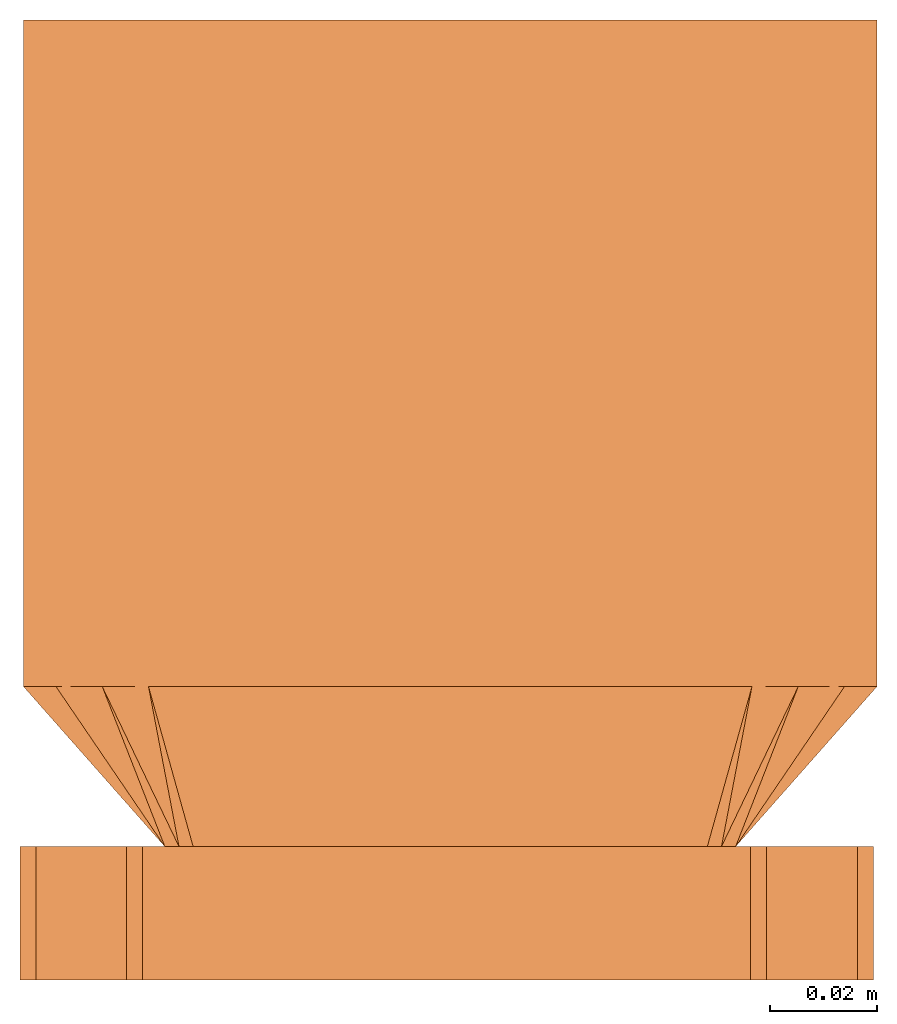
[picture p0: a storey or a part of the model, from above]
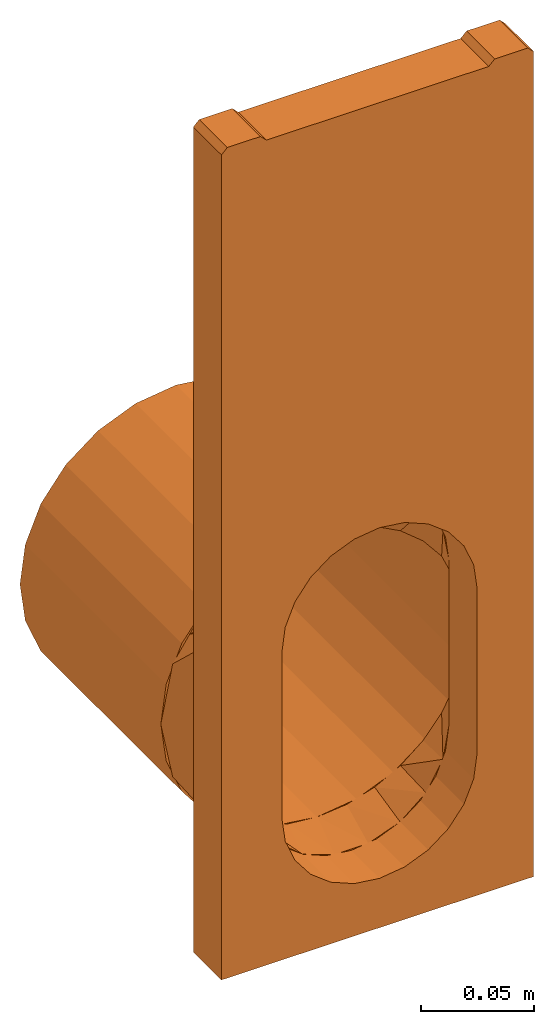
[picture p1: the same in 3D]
Properties of the parts of a building model (IFC2X3)

# File
Description: ViewDefinition [CoordinationView]
File name: 32508 - PD100 F 508 Inlet outlet endcap.ifc
Time: 2013-10-11T12:34:40
Written by: Autodesk Revit 2013
Made in: 20120221_2030(x64)

# IfcProject, Project Number
LongName: Project Name; Phase: Project Status

# IfcSite, Default
RefLatitude: 42, 21, 30, 344238; RefLongitude: -71, -3, -35, -194702; RefElevation: 0 mm

# IfcBuilding
Pset_BuildingCommon - NumberOfStoreys: 2
Other - Project Address: Enter address here; Project Name: Project Name; Project Issue Date: Issue Date; Project Status: Project Status; Client Name: Owner; Project Number: Project Number

# IfcBuildingStorey (2)
Constraints - Elevation Base: 0
Graphics - Symbol: M_Level Head - Circle: M_Level Head - Circle; Line Weight: 1; Color: 0; Line Pattern: Center; Symbol at End 2 Default: yes; Symbol at End 1 Default: no
Identity Data - Building Story: yes; Structural: no
Dimensions - Computation Height: 0 mm
Name | LongName = Name | Elevation (mm) = Constraints, Elevation (mm)
B.O. Footing | B.O. Footing | -4600
T.O. Footing | T.O. Footing | -4300

# IfcBuildingElementProxy: 32508 - PD100 F 508 Inlet/outlet endcap, Civil-Drainage-Channel-ACO-RoadDrain 100:32508 - PD100 F 508 Inlet/outlet endcap:32508 - PD100 F 508 Inlet/outlet endcap:310733
In: B.O. Footing
Material: Acetal Resin, Black
Other - CreatedBy: www.aco.co.uk; Revision: 1
Materials and Finishes - Channel Colour: N/A; Access Cover/Frame Material: N/A; Grating Colour: N/A; End Cap Colour: Black; End Cap Material: Vienite® Synthetic Resin Concrete; Grating Material: N/A; Connection Pipe Material: MDPE; Access Cover/Frame Colour: N/A; Access Cover/Frame Finish: N/A; Channel Material: N/A; Grating Finish: N/A; Connection Pipe Colour: Black
Dimensions - Custom Void Length: 0 mm; Length: 500 mm; Straight Void Length: 25 mm; Volume: 1530675 mm3; Void Depth: -450 mm; Invert Depth.: 175 mm; Straight Void Start: 0 mm; I/O End Cap Void: 228 mm; Total Depth: 250 mm
Constraints - Level: Level: T.O. Footing; Moves With Nearby Elements: no
Phasing - Phase Created: Phase 1
Pset_BuildingElementProxyCommon - Reference: 32508 - PD100 F 508 Inlet/outlet endcap
General - SerialNumber: 0.000000; TagNumber: 0.000000
Identity Data - Product brochure: http://www.aco.co.uk/download.php?id=256; Manufacturer: ACO Technologies plc - ACO Water Management Division; OmniClass Title: Rainwater Removal; Telephone: +44 (0)1462 816666; e-mail Technical: technical@aco.co.uk; Model: ACO RoadDrain 100 PD100F; Type Comments: ACO RoadDrain PD100 F 508 Inlet/Outlet End Cap; Watermark 1: This file is the property of ACO Technologies PLC; Address: ACO Business Park, Hitchin Road, Shefford, Bedfordshire, United Kingdom SG17 5TE; Price: POA - contact ACO; e-mail Sales: customersupport@aco.co.uk; Assembly Code: D2040; Cost: 0; Model Description: Monolithic Channel drainage system; OmniClass Number: 23.70.50.24; URL: www.aco.co.uk; Watermark 2: This file is water marked and users are prohibited to reproduce, adapt, distribute this information; Product Page URL: http://www.aco.co.uk/product_detail.php?id=21; Watermarked By: www.aco.co.uk; Watermarked With: BIM Manager Premium Suite; Assembly Description: Rain Water Drainage; Installation guidelines: http://www.aco.co.uk/download.php?id=256; Product Code: 32508; Fax: +44 (0)1462 815895; Maintenance guidelines: http://www.aco.co.uk/download.php?id=256
Green Building Properties - Access Cover/Frame Recycled Material Content: N/A; Access Cover/Frame Recyclable: N/A; Channel Recyclable: N/A; End Cap Recyclable: Fully recyclable; Grating Recycled Material Content: N/A; Channel Recycled Material Content: N/A; Grating Recyclable: N/A; End Cap Recycled Material Content: 20% minimum
Data - Product Weight: 3.0 Kg; Invert Depth: N/A; Product Dimensions: 25mm x 160mm x 450mm (LxWxH); Installation - Concrete Grade: N/A; Channel C.S.A: N/A; Connection Pipe O.D: Ø160mm; Product Standard: N/A; ACO Hydraulic Design Software: N/A; Concrete Surround Volume - Load Class F 900 - Concrete Pavement: N/A; Load Class: N/A; Hydraulic Performance: N/A
Construction - Closing End Cap: no; Inlet Outlet end cap_350 high: no; Grating 500mm: no; 32900 - Sump Unit: no; Access unit: no; Inlet Outlet end cap_450 high: yes; Channel 160mm Wide: no

# IfcOpeningElement: Recess
In: T.O. Footing
Dimensions - Volume: 47734143200 mm3; Thickness: 1550 mm; Perimeter: 22200 mm; Area: 30800000 mm2
Phasing - Phase Created: Phase 1
Constraints - Level: Level: T.O. Footing; Related to Mass: no; Room Bounding: yes; Height Offset From Level: 0 mm
Structural - Enable Analytical Model: no; Structural: no
Construction - Function: 0; Default Thickness: 1550 mm
Analytical Properties - Thermal Resistance (R): 1.79211; Heat Transfer Coefficient (U): 0.558; Roughness: 1; Thermal mass: 2039700; Absorptance: 0.1
Graphics - Coarse Scale Fill Color: 0
Materials and Finishes - Structural Material: Grass

# IfcSlab: Floor:Generic Floor - 400mm, Floor:Generic Floor - 400mm:136436
In: T.O. Footing
PredefinedType: FLOOR; Material: Grass 50 mm, Earth 1500 mm
Dimensions - Volume: 47734143200 mm3; Thickness: 1550 mm; Perimeter: 22200 mm; Area: 30800000 mm2
Phasing - Phase Created: Phase 1
Constraints - Level: Level: T.O. Footing; Related to Mass: no; Room Bounding: yes; Height Offset From Level: 0 mm
Structural - Enable Analytical Model: no; Structural: no
Pset_SlabCommon - Reference: Generic Floor - 400mm; IsExternal: no; LoadBearing: yes
Construction - Function: 0; Default Thickness: 1550 mm
Analytical Properties - Thermal Resistance (R): 1.79211; Heat Transfer Coefficient (U): 0.558; Roughness: 1; Thermal mass: 2039700; Absorptance: 0.1
Graphics - Coarse Scale Fill Color: 0
Materials and Finishes - Structural Material: Grass
